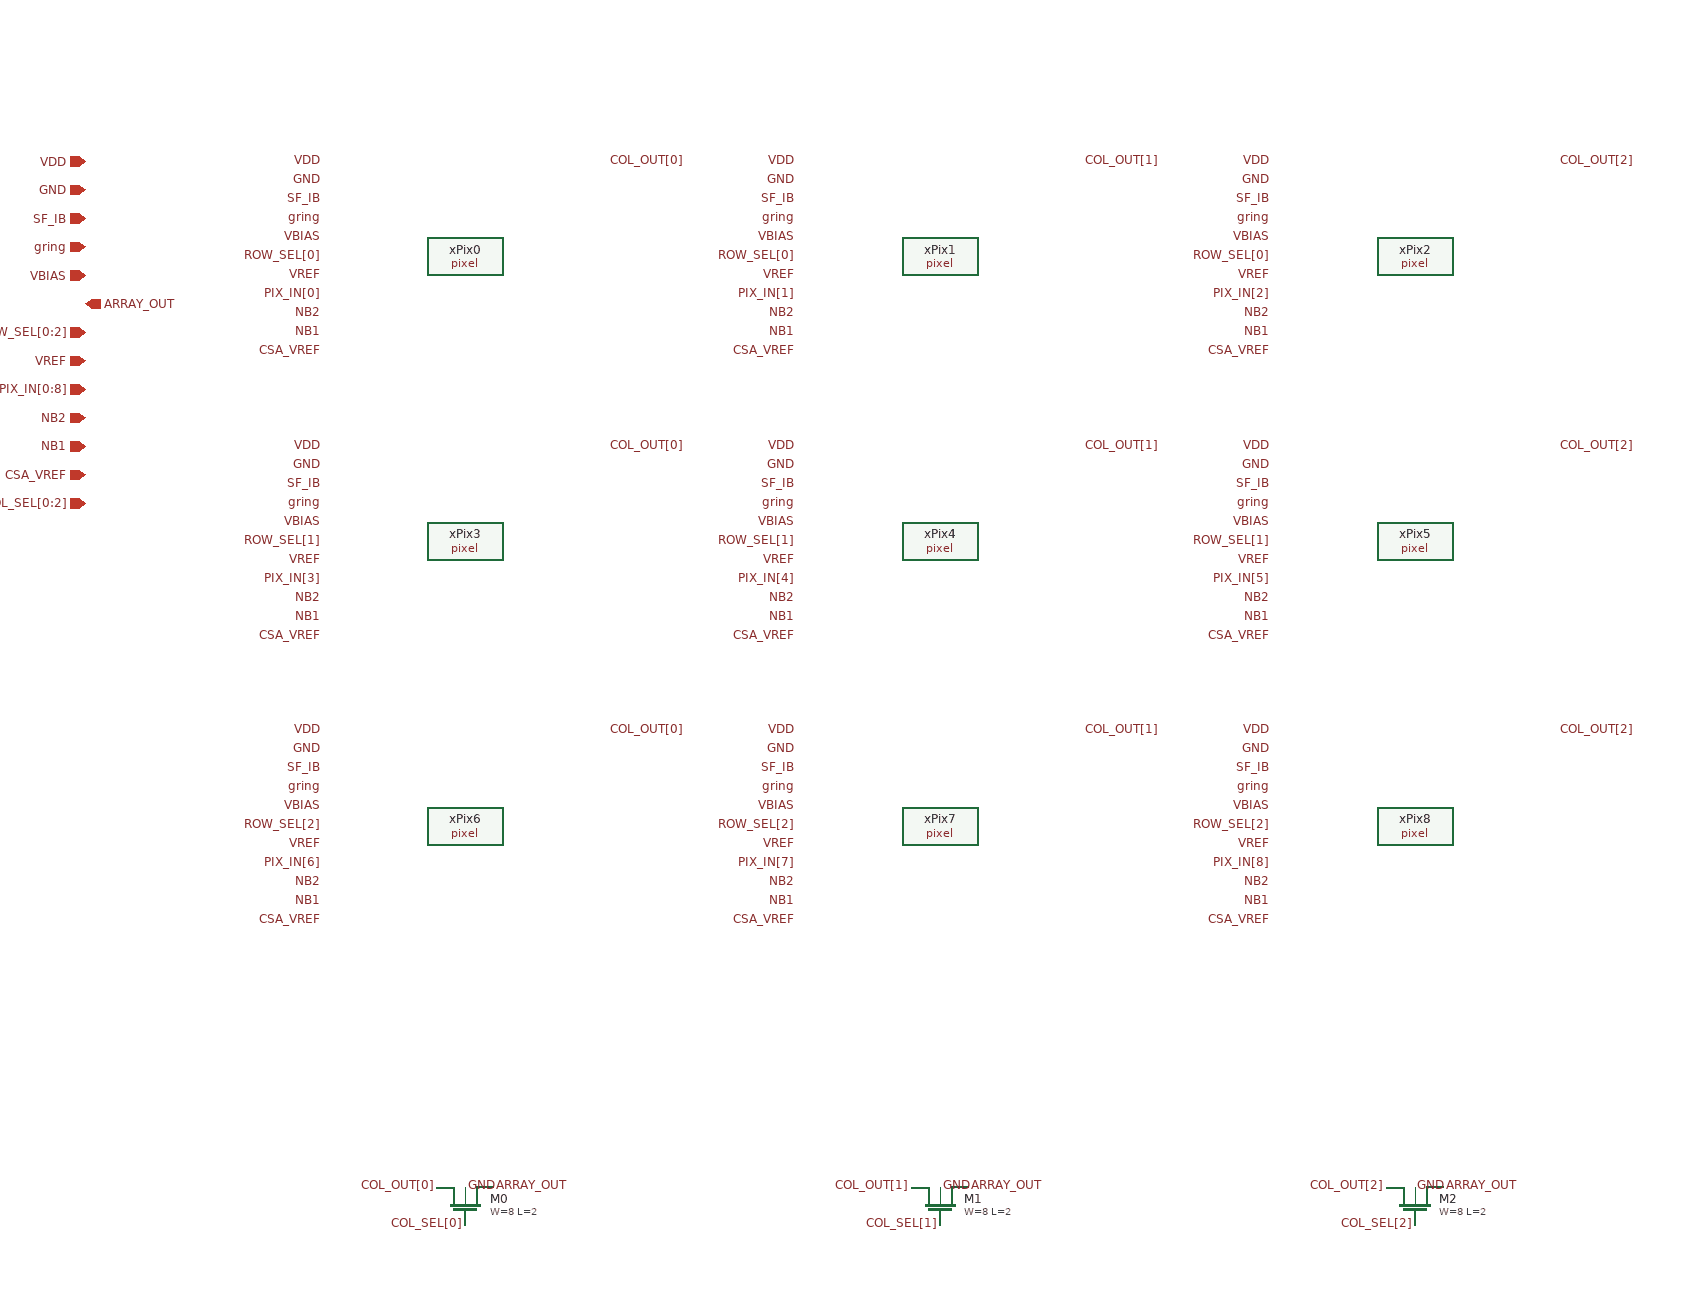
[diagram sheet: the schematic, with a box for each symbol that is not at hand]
v {xschem version=3.4.5 file_version=1.2
}
G {}
K {}
V {}
S {}
E {}
C {devices/netlist_options.sym} -100 -100 0 0 {bus_replacement_char="xx"
lvs_ignore=1}
C {devices/ipin.sym} -150 0 0 0 {name=p1 lab=VDD}
C {devices/ipin.sym} -150 30 0 0 {name=p2 lab=GND}
C {devices/ipin.sym} -150 60 0 0 {name=p3 lab=SF_IB}
C {devices/ipin.sym} -150 90 0 0 {name=p4 lab=gring}
C {devices/ipin.sym} -150 120 0 0 {name=p5 lab=VBIAS}
C {devices/opin.sym} -150 150 0 0 {name=p6 lab=ARRAY_OUT}
C {devices/ipin.sym} -150 180 0 0 {name=p7 lab=ROW_SEL[0:2]}
C {devices/ipin.sym} -150 210 0 0 {name=p8 lab=VREF}
C {devices/ipin.sym} -150 240 0 0 {name=p9 lab=PIX_IN[0:8]}
C {devices/ipin.sym} -150 270 0 0 {name=p10 lab=NB2}
C {devices/ipin.sym} -150 300 0 0 {name=p11 lab=NB1}
C {devices/ipin.sym} -150 330 0 0 {name=p12 lab=CSA_VREF}
C {devices/ipin.sym} -150 360 0 0 {name=p13 lab=COL_SEL[0:2]}
C {pixel/pixel.sym} 250 100 0 0 {name=xPix0}
C {devices/lab_pin.sym} 100 0 0 0 {name=p1 sig_type=std_logic lab=VDD}
C {devices/lab_pin.sym} 100 20 0 0 {name=p1 sig_type=std_logic lab=GND}
C {devices/lab_pin.sym} 100 40 0 0 {name=p1 sig_type=std_logic lab=SF_IB}
C {devices/lab_pin.sym} 100 60 0 0 {name=p1 sig_type=std_logic lab=gring}
C {devices/lab_pin.sym} 100 80 0 0 {name=p1 sig_type=std_logic lab=VBIAS}
C {devices/lab_pin.sym} 400 0 2 0 {name=p1 sig_type=std_logic lab=COL_OUT[0]}
C {devices/lab_pin.sym} 100 100 0 0 {name=p1 sig_type=std_logic lab=ROW_SEL[0]}
C {devices/lab_pin.sym} 100 120 0 0 {name=p1 sig_type=std_logic lab=VREF}
C {devices/lab_pin.sym} 100 140 0 0 {name=p1 sig_type=std_logic lab=PIX_IN[0]}
C {devices/lab_pin.sym} 100 160 0 0 {name=p1 sig_type=std_logic lab=NB2}
C {devices/lab_pin.sym} 100 180 0 0 {name=p1 sig_type=std_logic lab=NB1}
C {devices/lab_pin.sym} 100 200 0 0 {name=p1 sig_type=std_logic lab=CSA_VREF}
C {pixel/pixel.sym} 750 100 0 0 {name=xPix1}
C {devices/lab_pin.sym} 600 0 0 0 {name=p1 sig_type=std_logic lab=VDD}
C {devices/lab_pin.sym} 600 20 0 0 {name=p1 sig_type=std_logic lab=GND}
C {devices/lab_pin.sym} 600 40 0 0 {name=p1 sig_type=std_logic lab=SF_IB}
C {devices/lab_pin.sym} 600 60 0 0 {name=p1 sig_type=std_logic lab=gring}
C {devices/lab_pin.sym} 600 80 0 0 {name=p1 sig_type=std_logic lab=VBIAS}
C {devices/lab_pin.sym} 900 0 2 0 {name=p1 sig_type=std_logic lab=COL_OUT[1]}
C {devices/lab_pin.sym} 600 100 0 0 {name=p1 sig_type=std_logic lab=ROW_SEL[0]}
C {devices/lab_pin.sym} 600 120 0 0 {name=p1 sig_type=std_logic lab=VREF}
C {devices/lab_pin.sym} 600 140 0 0 {name=p1 sig_type=std_logic lab=PIX_IN[1]}
C {devices/lab_pin.sym} 600 160 0 0 {name=p1 sig_type=std_logic lab=NB2}
C {devices/lab_pin.sym} 600 180 0 0 {name=p1 sig_type=std_logic lab=NB1}
C {devices/lab_pin.sym} 600 200 0 0 {name=p1 sig_type=std_logic lab=CSA_VREF}
C {pixel/pixel.sym} 1250 100 0 0 {name=xPix2}
C {devices/lab_pin.sym} 1100 0 0 0 {name=p1 sig_type=std_logic lab=VDD}
C {devices/lab_pin.sym} 1100 20 0 0 {name=p1 sig_type=std_logic lab=GND}
C {devices/lab_pin.sym} 1100 40 0 0 {name=p1 sig_type=std_logic lab=SF_IB}
C {devices/lab_pin.sym} 1100 60 0 0 {name=p1 sig_type=std_logic lab=gring}
C {devices/lab_pin.sym} 1100 80 0 0 {name=p1 sig_type=std_logic lab=VBIAS}
C {devices/lab_pin.sym} 1400 0 2 0 {name=p1 sig_type=std_logic lab=COL_OUT[2]}
C {devices/lab_pin.sym} 1100 100 0 0 {name=p1 sig_type=std_logic lab=ROW_SEL[0]}
C {devices/lab_pin.sym} 1100 120 0 0 {name=p1 sig_type=std_logic lab=VREF}
C {devices/lab_pin.sym} 1100 140 0 0 {name=p1 sig_type=std_logic lab=PIX_IN[2]}
C {devices/lab_pin.sym} 1100 160 0 0 {name=p1 sig_type=std_logic lab=NB2}
C {devices/lab_pin.sym} 1100 180 0 0 {name=p1 sig_type=std_logic lab=NB1}
C {devices/lab_pin.sym} 1100 200 0 0 {name=p1 sig_type=std_logic lab=CSA_VREF}
C {pixel/pixel.sym} 250 400 0 0 {name=xPix3}
C {devices/lab_pin.sym} 100 300 0 0 {name=p1 sig_type=std_logic lab=VDD}
C {devices/lab_pin.sym} 100 320 0 0 {name=p1 sig_type=std_logic lab=GND}
C {devices/lab_pin.sym} 100 340 0 0 {name=p1 sig_type=std_logic lab=SF_IB}
C {devices/lab_pin.sym} 100 360 0 0 {name=p1 sig_type=std_logic lab=gring}
C {devices/lab_pin.sym} 100 380 0 0 {name=p1 sig_type=std_logic lab=VBIAS}
C {devices/lab_pin.sym} 400 300 2 0 {name=p1 sig_type=std_logic lab=COL_OUT[0]}
C {devices/lab_pin.sym} 100 400 0 0 {name=p1 sig_type=std_logic lab=ROW_SEL[1]}
C {devices/lab_pin.sym} 100 420 0 0 {name=p1 sig_type=std_logic lab=VREF}
C {devices/lab_pin.sym} 100 440 0 0 {name=p1 sig_type=std_logic lab=PIX_IN[3]}
C {devices/lab_pin.sym} 100 460 0 0 {name=p1 sig_type=std_logic lab=NB2}
C {devices/lab_pin.sym} 100 480 0 0 {name=p1 sig_type=std_logic lab=NB1}
C {devices/lab_pin.sym} 100 500 0 0 {name=p1 sig_type=std_logic lab=CSA_VREF}
C {pixel/pixel.sym} 750 400 0 0 {name=xPix4}
C {devices/lab_pin.sym} 600 300 0 0 {name=p1 sig_type=std_logic lab=VDD}
C {devices/lab_pin.sym} 600 320 0 0 {name=p1 sig_type=std_logic lab=GND}
C {devices/lab_pin.sym} 600 340 0 0 {name=p1 sig_type=std_logic lab=SF_IB}
C {devices/lab_pin.sym} 600 360 0 0 {name=p1 sig_type=std_logic lab=gring}
C {devices/lab_pin.sym} 600 380 0 0 {name=p1 sig_type=std_logic lab=VBIAS}
C {devices/lab_pin.sym} 900 300 2 0 {name=p1 sig_type=std_logic lab=COL_OUT[1]}
C {devices/lab_pin.sym} 600 400 0 0 {name=p1 sig_type=std_logic lab=ROW_SEL[1]}
C {devices/lab_pin.sym} 600 420 0 0 {name=p1 sig_type=std_logic lab=VREF}
C {devices/lab_pin.sym} 600 440 0 0 {name=p1 sig_type=std_logic lab=PIX_IN[4]}
C {devices/lab_pin.sym} 600 460 0 0 {name=p1 sig_type=std_logic lab=NB2}
C {devices/lab_pin.sym} 600 480 0 0 {name=p1 sig_type=std_logic lab=NB1}
C {devices/lab_pin.sym} 600 500 0 0 {name=p1 sig_type=std_logic lab=CSA_VREF}
C {pixel/pixel.sym} 1250 400 0 0 {name=xPix5}
C {devices/lab_pin.sym} 1100 300 0 0 {name=p1 sig_type=std_logic lab=VDD}
C {devices/lab_pin.sym} 1100 320 0 0 {name=p1 sig_type=std_logic lab=GND}
C {devices/lab_pin.sym} 1100 340 0 0 {name=p1 sig_type=std_logic lab=SF_IB}
C {devices/lab_pin.sym} 1100 360 0 0 {name=p1 sig_type=std_logic lab=gring}
C {devices/lab_pin.sym} 1100 380 0 0 {name=p1 sig_type=std_logic lab=VBIAS}
C {devices/lab_pin.sym} 1400 300 2 0 {name=p1 sig_type=std_logic lab=COL_OUT[2]}
C {devices/lab_pin.sym} 1100 400 0 0 {name=p1 sig_type=std_logic lab=ROW_SEL[1]}
C {devices/lab_pin.sym} 1100 420 0 0 {name=p1 sig_type=std_logic lab=VREF}
C {devices/lab_pin.sym} 1100 440 0 0 {name=p1 sig_type=std_logic lab=PIX_IN[5]}
C {devices/lab_pin.sym} 1100 460 0 0 {name=p1 sig_type=std_logic lab=NB2}
C {devices/lab_pin.sym} 1100 480 0 0 {name=p1 sig_type=std_logic lab=NB1}
C {devices/lab_pin.sym} 1100 500 0 0 {name=p1 sig_type=std_logic lab=CSA_VREF}
C {pixel/pixel.sym} 250 700 0 0 {name=xPix6}
C {devices/lab_pin.sym} 100 600 0 0 {name=p1 sig_type=std_logic lab=VDD}
C {devices/lab_pin.sym} 100 620 0 0 {name=p1 sig_type=std_logic lab=GND}
C {devices/lab_pin.sym} 100 640 0 0 {name=p1 sig_type=std_logic lab=SF_IB}
C {devices/lab_pin.sym} 100 660 0 0 {name=p1 sig_type=std_logic lab=gring}
C {devices/lab_pin.sym} 100 680 0 0 {name=p1 sig_type=std_logic lab=VBIAS}
C {devices/lab_pin.sym} 400 600 2 0 {name=p1 sig_type=std_logic lab=COL_OUT[0]}
C {devices/lab_pin.sym} 100 700 0 0 {name=p1 sig_type=std_logic lab=ROW_SEL[2]}
C {devices/lab_pin.sym} 100 720 0 0 {name=p1 sig_type=std_logic lab=VREF}
C {devices/lab_pin.sym} 100 740 0 0 {name=p1 sig_type=std_logic lab=PIX_IN[6]}
C {devices/lab_pin.sym} 100 760 0 0 {name=p1 sig_type=std_logic lab=NB2}
C {devices/lab_pin.sym} 100 780 0 0 {name=p1 sig_type=std_logic lab=NB1}
C {devices/lab_pin.sym} 100 800 0 0 {name=p1 sig_type=std_logic lab=CSA_VREF}
C {pixel/pixel.sym} 750 700 0 0 {name=xPix7}
C {devices/lab_pin.sym} 600 600 0 0 {name=p1 sig_type=std_logic lab=VDD}
C {devices/lab_pin.sym} 600 620 0 0 {name=p1 sig_type=std_logic lab=GND}
C {devices/lab_pin.sym} 600 640 0 0 {name=p1 sig_type=std_logic lab=SF_IB}
C {devices/lab_pin.sym} 600 660 0 0 {name=p1 sig_type=std_logic lab=gring}
C {devices/lab_pin.sym} 600 680 0 0 {name=p1 sig_type=std_logic lab=VBIAS}
C {devices/lab_pin.sym} 900 600 2 0 {name=p1 sig_type=std_logic lab=COL_OUT[1]}
C {devices/lab_pin.sym} 600 700 0 0 {name=p1 sig_type=std_logic lab=ROW_SEL[2]}
C {devices/lab_pin.sym} 600 720 0 0 {name=p1 sig_type=std_logic lab=VREF}
C {devices/lab_pin.sym} 600 740 0 0 {name=p1 sig_type=std_logic lab=PIX_IN[7]}
C {devices/lab_pin.sym} 600 760 0 0 {name=p1 sig_type=std_logic lab=NB2}
C {devices/lab_pin.sym} 600 780 0 0 {name=p1 sig_type=std_logic lab=NB1}
C {devices/lab_pin.sym} 600 800 0 0 {name=p1 sig_type=std_logic lab=CSA_VREF}
C {pixel/pixel.sym} 1250 700 0 0 {name=xPix8}
C {devices/lab_pin.sym} 1100 600 0 0 {name=p1 sig_type=std_logic lab=VDD}
C {devices/lab_pin.sym} 1100 620 0 0 {name=p1 sig_type=std_logic lab=GND}
C {devices/lab_pin.sym} 1100 640 0 0 {name=p1 sig_type=std_logic lab=SF_IB}
C {devices/lab_pin.sym} 1100 660 0 0 {name=p1 sig_type=std_logic lab=gring}
C {devices/lab_pin.sym} 1100 680 0 0 {name=p1 sig_type=std_logic lab=VBIAS}
C {devices/lab_pin.sym} 1400 600 2 0 {name=p1 sig_type=std_logic lab=COL_OUT[2]}
C {devices/lab_pin.sym} 1100 700 0 0 {name=p1 sig_type=std_logic lab=ROW_SEL[2]}
C {devices/lab_pin.sym} 1100 720 0 0 {name=p1 sig_type=std_logic lab=VREF}
C {devices/lab_pin.sym} 1100 740 0 0 {name=p1 sig_type=std_logic lab=PIX_IN[8]}
C {devices/lab_pin.sym} 1100 760 0 0 {name=p1 sig_type=std_logic lab=NB2}
C {devices/lab_pin.sym} 1100 780 0 0 {name=p1 sig_type=std_logic lab=NB1}
C {devices/lab_pin.sym} 1100 800 0 0 {name=p1 sig_type=std_logic lab=CSA_VREF}
C {sky130_fd_pr/nfet_01v8_lvt.sym} 250 1100 3 0 {name=M0
L=2 W=8 nf=1 mult=1
ad="'int((nf+1)/2) * W/nf * 0.29'" pd="'2*int((nf+1)/2) * (W/nf + 0.29)'" 
as="'int((nf+2)/2) * W/nf * 0.29'" 
ps="'2*int((nf+2)/2) * (W/nf + 0.29)'"
nrd="'0.29 / W'" nrs="'0.29 / W'" 
sa=0 sb=0 sd=0 model=nfet_01v8_lvt spiceprefix=X}
C {devices/lab_pin.sym} 220 1080 2 1 {name=col0 sig_type=std_logic, lab=COL_OUT[0]}
C {devices/lab_pin.sym} 250 1120 3 0 {name=col1 sig_type=std_logic, lab=COL_SEL[0]}
C {devices/lab_pin.sym} 280 1080 2 0 {name=col2 sig_type=std_logic, lab=ARRAY_OUT}
C {devices/lab_pin.sym} 250 1080 2 0 {name=col2 sig_type=std_logic, lab=GND}
C {sky130_fd_pr/nfet_01v8_lvt.sym} 750 1100 3 0 {name=M1
L=2 W=8 nf=1 mult=1
ad="'int((nf+1)/2) * W/nf * 0.29'" pd="'2*int((nf+1)/2) * (W/nf + 0.29)'" 
as="'int((nf+2)/2) * W/nf * 0.29'" 
ps="'2*int((nf+2)/2) * (W/nf + 0.29)'"
nrd="'0.29 / W'" nrs="'0.29 / W'" 
sa=0 sb=0 sd=0 model=nfet_01v8_lvt spiceprefix=X}
C {devices/lab_pin.sym} 720 1080 2 1 {name=col1 sig_type=std_logic, lab=COL_OUT[1]}
C {devices/lab_pin.sym} 750 1120 3 0 {name=col2 sig_type=std_logic, lab=COL_SEL[1]}
C {devices/lab_pin.sym} 780 1080 2 0 {name=col3 sig_type=std_logic, lab=ARRAY_OUT}
C {devices/lab_pin.sym} 750 1080 2 0 {name=col3 sig_type=std_logic, lab=GND}
C {sky130_fd_pr/nfet_01v8_lvt.sym} 1250 1100 3 0 {name=M2
L=2 W=8 nf=1 mult=1
ad="'int((nf+1)/2) * W/nf * 0.29'" pd="'2*int((nf+1)/2) * (W/nf + 0.29)'" 
as="'int((nf+2)/2) * W/nf * 0.29'" 
ps="'2*int((nf+2)/2) * (W/nf + 0.29)'"
nrd="'0.29 / W'" nrs="'0.29 / W'" 
sa=0 sb=0 sd=0 model=nfet_01v8_lvt spiceprefix=X}
C {devices/lab_pin.sym} 1220 1080 2 1 {name=col2 sig_type=std_logic, lab=COL_OUT[2]}
C {devices/lab_pin.sym} 1250 1120 3 0 {name=col3 sig_type=std_logic, lab=COL_SEL[2]}
C {devices/lab_pin.sym} 1280 1080 2 0 {name=col4 sig_type=std_logic, lab=ARRAY_OUT}
C {devices/lab_pin.sym} 1250 1080 2 0 {name=col4 sig_type=std_logic, lab=GND}
